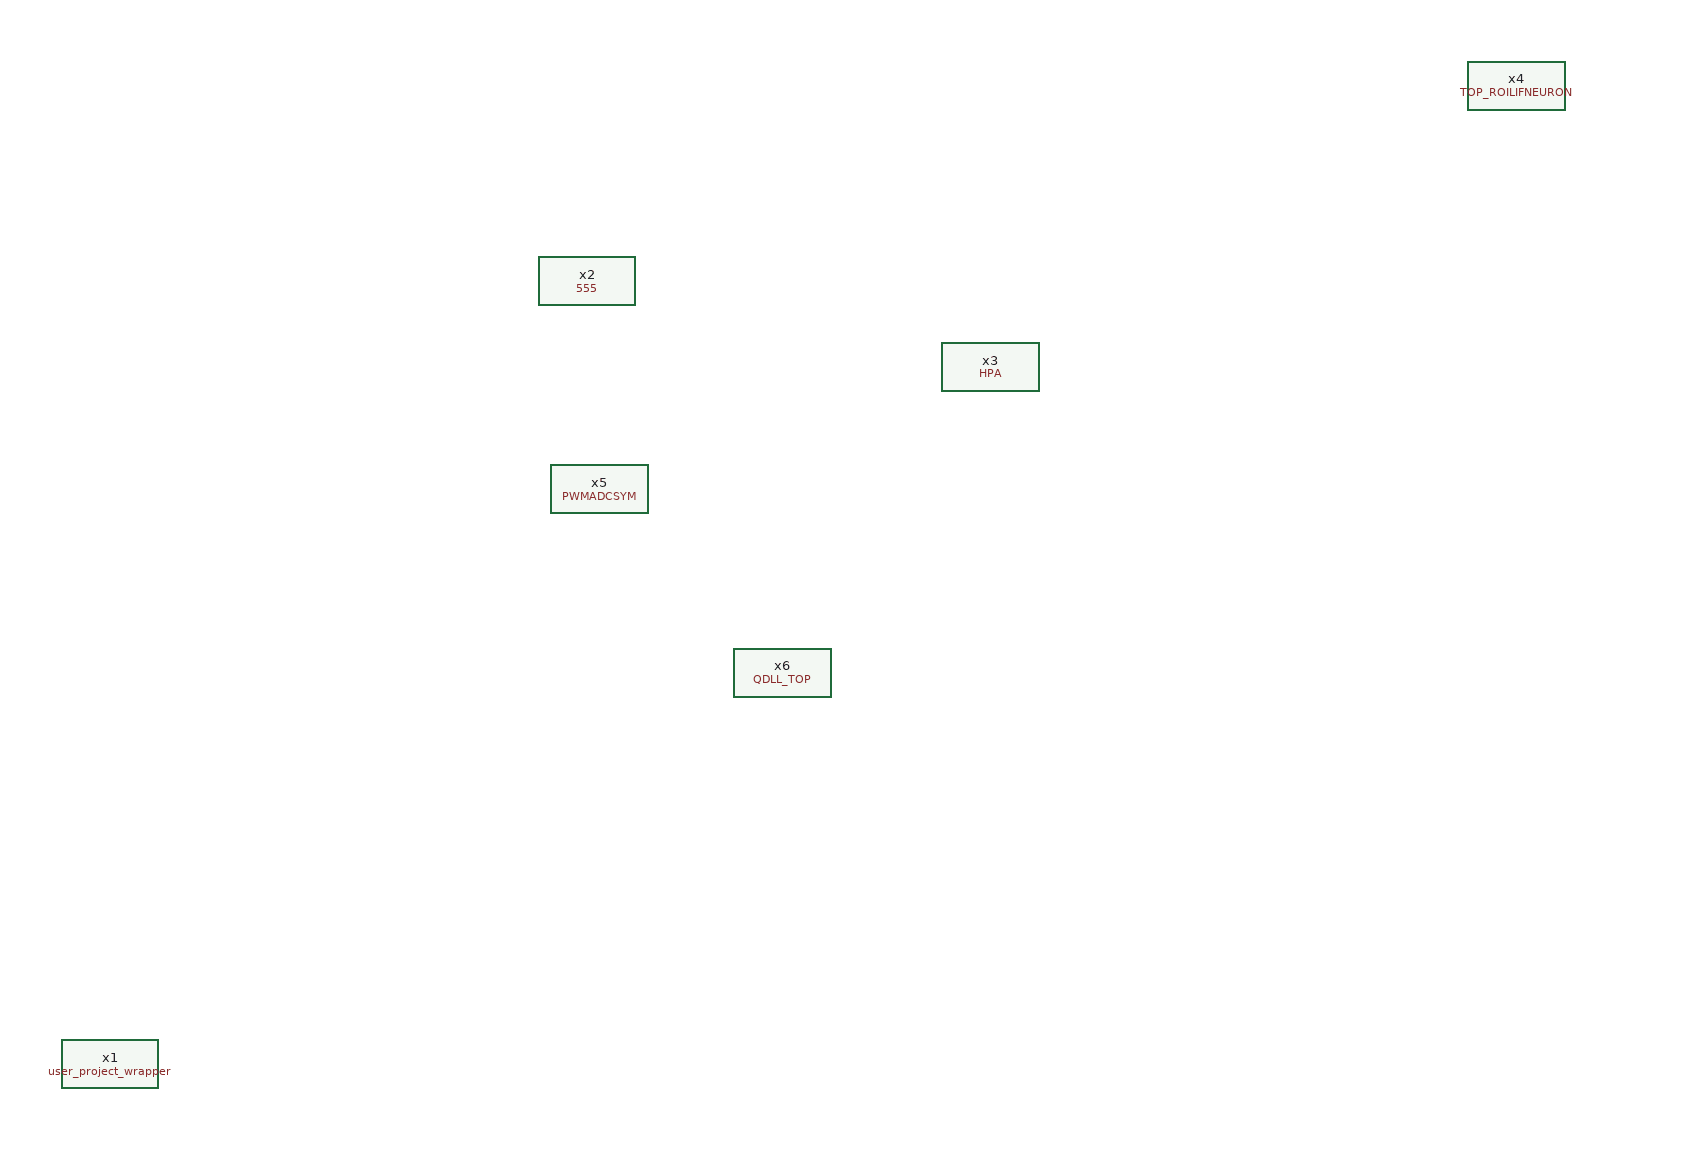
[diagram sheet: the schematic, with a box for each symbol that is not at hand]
v {xschem version=3.4.6 file_version=1.2}
G {}
K {}
V {}
S {}
E {}
C {IHP__MPC0349/MPC0349-main/schematic/xschem/user_project_wrapper.sym} 0 -40 0 0 {name=x1}
C {IHP__MPC0349/dependencies/IHP__OSC3593/OSC3593-main/schematic/xschem/555.sym} 390 -680 0 0 {name=x2}
C {IHP__MPC0349/dependencies/IHP__OPA2251/OPA2251-main/schematic/xschem/HPA.sym} 720 -610 0 0 {name=x3}
C {IHP__MPC0349/dependencies/IHP__OSC9996/OSC9996-main/schematic/xschem/TOP_ROILIFNEURON.sym} 1150 -840 0 0 {name=x4}
C {IHP__MPC0349/dependencies/IHP__QDLL6501/QDLL6501-main/schematic/xschem/QDLL_TOP.sym} 550 -360 0 0 {name=x6}
C {IHP__MPC0349/dependencies/IHP__OSC3593/OSC3593-main/schematic/xschem/PWMADCSYM.sym} 400 -510 0 0 {name=x5}
